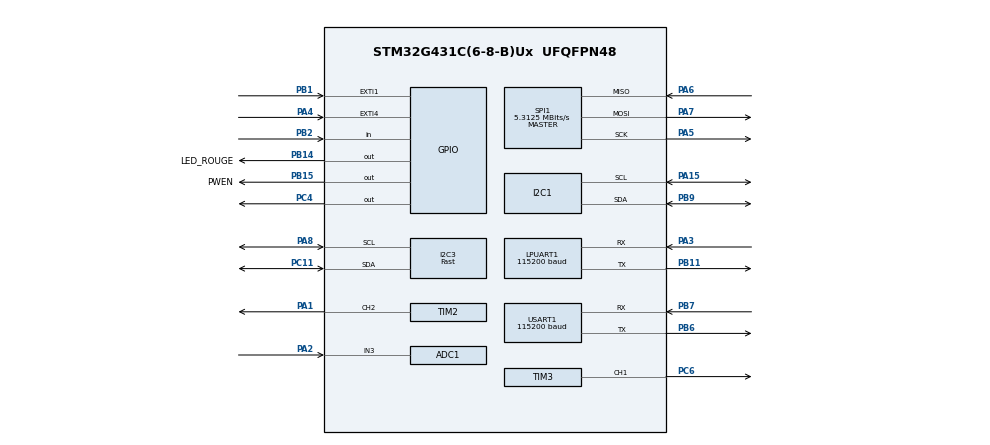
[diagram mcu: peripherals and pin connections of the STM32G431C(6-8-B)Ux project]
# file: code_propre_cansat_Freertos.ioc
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ADC1.Channel-0\#ChannelRegularConversion=ADC_CHANNEL_VREFINT
ADC1.Channel-1\#ChannelRegularConversion=ADC_CHANNEL_TEMPSENSOR_ADC1
ADC1.Channel-2\#ChannelRegularConversion=ADC_CHANNEL_3
ADC1.ContinuousConvMode=ENABLE
ADC1.EOCSelection=ADC_EOC_SEQ_CONV
ADC1.NbrOfConversion=3
ADC1.NbrOfConversionFlag=1
ADC1.OffsetNumber-0\#ChannelRegularConversion=ADC_OFFSET_NONE
ADC1.OffsetNumber-1\#ChannelRegularConversion=ADC_OFFSET_NONE
ADC1.OffsetNumber-2\#ChannelRegularConversion=ADC_OFFSET_NONE
ADC1.Rank-0\#ChannelRegularConversion=1
ADC1.Rank-1\#ChannelRegularConversion=2
ADC1.Rank-2\#ChannelRegularConversion=3
ADC1.SamplingTime-0\#ChannelRegularConversion=ADC_SAMPLETIME_640CYCLES_5
ADC1.SamplingTime-1\#ChannelRegularConversion=ADC_SAMPLETIME_640CYCLES_5
ADC1.SamplingTime-2\#ChannelRegularConversion=ADC_SAMPLETIME_640CYCLES_5
ADC1.master=1
Dma.ADC1.0.Direction=DMA_PERIPH_TO_MEMORY
Dma.ADC1.0.EventEnable=DISABLE
Dma.ADC1.0.Instance=DMA1_Channel2
Dma.ADC1.0.MemDataAlignment=DMA_MDATAALIGN_HALFWORD
Dma.ADC1.0.MemInc=DMA_MINC_ENABLE
Dma.ADC1.0.Mode=DMA_CIRCULAR
Dma.ADC1.0.PeriphDataAlignment=DMA_PDATAALIGN_HALFWORD
Dma.ADC1.0.PeriphInc=DMA_PINC_DISABLE
Dma.ADC1.0.Polarity=HAL_DMAMUX_REQ_GEN_RISING
Dma.ADC1.0.Priority=DMA_PRIORITY_LOW
Dma.ADC1.0.RequestNumber=1
Dma.ADC1.0.SignalID=NONE
Dma.ADC1.0.SyncEnable=DISABLE
Dma.ADC1.0.SyncPolarity=HAL_DMAMUX_SYNC_NO_EVENT
Dma.ADC1.0.SyncRequestNumber=1
Dma.ADC1.0.SyncSignalID=NONE
Dma.LPUART1_RX.1.Direction=DMA_PERIPH_TO_MEMORY
Dma.LPUART1_RX.1.EventEnable=DISABLE
Dma.LPUART1_RX.1.Instance=DMA1_Channel3
Dma.LPUART1_RX.1.MemDataAlignment=DMA_MDATAALIGN_BYTE
Dma.LPUART1_RX.1.MemInc=DMA_MINC_ENABLE
Dma.LPUART1_RX.1.Mode=DMA_CIRCULAR
Dma.LPUART1_RX.1.PeriphDataAlignment=DMA_PDATAALIGN_BYTE
Dma.LPUART1_RX.1.PeriphInc=DMA_PINC_DISABLE
Dma.LPUART1_RX.1.Polarity=HAL_DMAMUX_REQ_GEN_RISING
Dma.LPUART1_RX.1.Priority=DMA_PRIORITY_LOW
Dma.LPUART1_RX.1.RequestNumber=1
Dma.LPUART1_RX.1.SignalID=NONE
Dma.LPUART1_RX.1.SyncEnable=DISABLE
Dma.LPUART1_RX.1.SyncPolarity=HAL_DMAMUX_SYNC_NO_EVENT
Dma.LPUART1_RX.1.SyncRequestNumber=1
Dma.LPUART1_RX.1.SyncSignalID=NONE
Dma.LPUART1_TX.4.Direction=DMA_MEMORY_TO_PERIPH
Dma.LPUART1_TX.4.EventEnable=DISABLE
Dma.LPUART1_TX.4.Instance=DMA1_Channel4
Dma.LPUART1_TX.4.MemDataAlignment=DMA_MDATAALIGN_BYTE
Dma.LPUART1_TX.4.MemInc=DMA_MINC_ENABLE
Dma.LPUART1_TX.4.Mode=DMA_NORMAL
Dma.LPUART1_TX.4.PeriphDataAlignment=DMA_PDATAALIGN_BYTE
Dma.LPUART1_TX.4.PeriphInc=DMA_PINC_DISABLE
Dma.LPUART1_TX.4.Polarity=HAL_DMAMUX_REQ_GEN_RISING
Dma.LPUART1_TX.4.Priority=DMA_PRIORITY_LOW
Dma.LPUART1_TX.4.RequestNumber=1
Dma.LPUART1_TX.4.SignalID=NONE
Dma.LPUART1_TX.4.SyncEnable=DISABLE
Dma.LPUART1_TX.4.SyncPolarity=HAL_DMAMUX_SYNC_NO_EVENT
Dma.LPUART1_TX.4.SyncRequestNumber=1
Dma.LPUART1_TX.4.SyncSignalID=NONE
Dma.Request0=ADC1
Dma.Request1=LPUART1_RX
Dma.Request2=USART1_RX
Dma.Request3=TIM2_CH2
Dma.Request4=LPUART1_TX
Dma.TIM2_CH2.3.Direction=DMA_MEMORY_TO_PERIPH
Dma.TIM2_CH2.3.EventEnable=DISABLE
Dma.TIM2_CH2.3.Instance=DMA1_Channel1
Dma.TIM2_CH2.3.MemDataAlignment=DMA_MDATAALIGN_BYTE
Dma.TIM2_CH2.3.MemInc=DMA_MINC_ENABLE
Dma.TIM2_CH2.3.Mode=DMA_NORMAL
Dma.TIM2_CH2.3.PeriphDataAlignment=DMA_PDATAALIGN_WORD
Dma.TIM2_CH2.3.PeriphInc=DMA_PINC_DISABLE
Dma.TIM2_CH2.3.Polarity=HAL_DMAMUX_REQ_GEN_RISING
Dma.TIM2_CH2.3.Priority=DMA_PRIORITY_LOW
Dma.TIM2_CH2.3.RequestNumber=1
Dma.TIM2_CH2.3.SignalID=NONE
Dma.TIM2_CH2.3.SyncEnable=DISABLE
Dma.TIM2_CH2.3.SyncPolarity=HAL_DMAMUX_SYNC_NO_EVENT
Dma.TIM2_CH2.3.SyncRequestNumber=1
Dma.TIM2_CH2.3.SyncSignalID=NONE
Dma.USART1_RX.2.Direction=DMA_PERIPH_TO_MEMORY
Dma.USART1_RX.2.EventEnable=DISABLE
Dma.USART1_RX.2.Instance=DMA1_Channel5
Dma.USART1_RX.2.MemDataAlignment=DMA_MDATAALIGN_BYTE
Dma.USART1_RX.2.MemInc=DMA_MINC_ENABLE
Dma.USART1_RX.2.Mode=DMA_CIRCULAR
Dma.USART1_RX.2.PeriphDataAlignment=DMA_PDATAALIGN_BYTE
Dma.USART1_RX.2.PeriphInc=DMA_PINC_DISABLE
Dma.USART1_RX.2.Polarity=HAL_DMAMUX_REQ_GEN_RISING
Dma.USART1_RX.2.Priority=DMA_PRIORITY_LOW
Dma.USART1_RX.2.RequestNumber=1
Dma.USART1_RX.2.SignalID=NONE
Dma.USART1_RX.2.SyncEnable=DISABLE
Dma.USART1_RX.2.SyncPolarity=HAL_DMAMUX_SYNC_NO_EVENT
Dma.USART1_RX.2.SyncRequestNumber=1
Dma.USART1_RX.2.SyncSignalID=NONE
FATFS._MAX_SS=512
FATFS._USE_LFN=0
FREERTOS.BinarySemaphores01=uartTxDone,Dynamic,NULL,Available
FREERTOS.INCLUDE_vTaskDelayUntil=1
FREERTOS.Mutexes01=SDCard_mutexe,Dynamic,NULL,Depleted;I2Cmutex,Dynamic,NULL,Depleted;uartmutex,Dynamic,NULL,Available
FREERTOS.Tasks01=statemachine,1,300,Startstatemachine,Default,NULL,Dynamic,NULL,NULL;GNSSParse,0,256,StartGNSSParse,Default,NULL,Dynamic,NULL,NULL;Sdcardwrite,0,512,StartSdcard,Default,NULL,Dynamic,NULL,NULL;servo,1,256,Startservo,Default,NULL,Dynamic,NULL,NULL;distancecalc,-1,256,Startdistancecalc,Default,NULL,Dynamic,NULL,NULL;tarvosDecode,3,256,startTarvosDecode,Default,NULL,Dynamic,NULL,NULL
FREERTOS.configENABLE_FPU=1
FREERTOS.configTOTAL_HEAP_SIZE=12000
FREERTOS.configUSE_NEWLIB_REENTRANT=1
I2C1.Timing=0x40B285C2
I2C3.I2C_Speed_Mode=I2C_Fast
I2C3.Timing=0x40621236
LPUART1.BaudRate=115200
Mcu.Family=STM32G4
Mcu.Name=STM32G431C(6-8-B)Ux
Mcu.Package=UFQFPN48
NVIC.ADC1_2_IRQn=true\:5\:0\:false\:false\:true\:true\:true\:true\:true
NVIC.DMA1_Channel1_IRQn=true\:5\:0\:false\:false\:true\:true\:false\:true\:true
NVIC.DMA1_Channel2_IRQn=true\:5\:0\:false\:false\:true\:true\:false\:true\:true
NVIC.DMA1_Channel3_IRQn=true\:5\:0\:false\:false\:true\:true\:false\:true\:true
NVIC.DMA1_Channel4_IRQn=true\:5\:0\:false\:false\:true\:true\:false\:true\:true
NVIC.DMA1_Channel5_IRQn=true\:5\:0\:false\:false\:true\:true\:false\:true\:true
NVIC.EXTI1_IRQn=true\:5\:0\:false\:false\:true\:true\:true\:true\:true
NVIC.EXTI4_IRQn=true\:5\:0\:false\:false\:true\:true\:true\:true\:true
NVIC.LPUART1_IRQn=true\:5\:0\:false\:false\:true\:true\:true\:true\:true
NVIC.PriorityGroup=NVIC_PRIORITYGROUP_4
NVIC.TIM1_UP_TIM16_IRQn=true\:15\:0\:false\:false\:true\:false\:false\:true\:true
NVIC.TIM2_IRQn=true\:5\:0\:false\:false\:true\:true\:true\:true\:true
NVIC.TIM4_IRQn=true\:6\:0\:true\:false\:true\:true\:true\:true\:true
NVIC.TimeBase=TIM1_UP_TIM16_IRQn
NVIC.TimeBaseIP=TIM1
NVIC.USART1_IRQn=true\:5\:0\:false\:false\:true\:true\:true\:true\:true
PA1.GPIO_Speed=GPIO_SPEED_FREQ_MEDIUM
PA1.Signal=S_TIM2_CH2
PA13.Mode=Trace_Asynchronous_SW
PA13.Signal=SYS_JTMS-SWDIO
PA14.Mode=Trace_Asynchronous_SW
PA14.Signal=SYS_JTCK-SWCLK
PA15.Mode=I2C
PA15.Signal=I2C1_SCL
PA2.Mode=IN3-Single-Ended
PA2.Signal=ADC1_IN3
PA3.Mode=Asynchronous
PA3.Signal=LPUART1_RX
PA4.GPIO_ModeDefaultEXTI=GPIO_MODE_IT_RISING_FALLING
PA4.Signal=GPXTI4
PA5.GPIO_PuPd=GPIO_NOPULL
PA5.Mode=Full_Duplex_Master
PA5.Signal=SPI1_SCK
PA6.GPIO_PuPd=GPIO_NOPULL
PA6.Mode=Full_Duplex_Master
PA6.Signal=SPI1_MISO
PA7.GPIO_PuPd=GPIO_NOPULL
PA7.Mode=Full_Duplex_Master
PA7.Signal=SPI1_MOSI
PA8.Mode=I2C
PA8.Signal=I2C3_SCL
PB1.GPIO_ModeDefaultEXTI=GPIO_MODE_IT_RISING_FALLING
PB1.GPIO_PuPd=GPIO_NOPULL
PB1.Signal=GPXTI1
PB11.Mode=Asynchronous
PB11.Signal=LPUART1_TX
PB14.GPIO_Label=LED_ROUGE
PB14.Signal=GPIO_Output
PB15.GPIO_Label=PWEN
PB15.Signal=GPIO_Output
PB2.Signal=GPIO_Input
PB3.Mode=Trace_Asynchronous_SW
PB3.Signal=SYS_JTDO-SWO
PB6.Mode=Asynchronous
PB6.Signal=USART1_TX
PB7.Mode=Asynchronous
PB7.Signal=USART1_RX
PB9.Mode=I2C
PB9.Signal=I2C1_SDA
PC11.Mode=I2C
PC11.Signal=I2C3_SDA
PC4.Signal=GPIO_Output
PC6.Signal=S_TIM3_CH1
PF0-OSC_IN.Mode=HSE-External-Oscillator
PF0-OSC_IN.Signal=RCC_OSC_IN
PF1-OSC_OUT.Mode=HSE-External-Oscillator
PF1-OSC_OUT.Signal=RCC_OSC_OUT
ProjectManager.HeapSize=0x200
ProjectManager.StackSize=0x400
ProjectManager.TargetToolchain=STM32CubeIDE
RCC.ADC12Freq_Value=170000000
RCC.AHBFreq_Value=170000000
RCC.APB1Freq_Value=170000000
RCC.APB1TimFreq_Value=170000000
RCC.APB2Freq_Value=170000000
RCC.APB2TimFreq_Value=170000000
RCC.CortexFreq_Value=170000000
RCC.EXTERNAL_CLOCK_VALUE=12288000
RCC.HCLKFreq_Value=170000000
RCC.HSE_VALUE=16000000
RCC.HSI48_VALUE=48000000
RCC.HSI_VALUE=16000000
RCC.LSE_VALUE=32768
RCC.PLLM=RCC_PLLM_DIV4
RCC.PLLN=85
RCC.PLLSourceVirtual=RCC_PLLSOURCE_HSE
RCC.SYSCLKFreq_VALUE=170000000
RCC.SYSCLKSource=RCC_SYSCLKSOURCE_PLLCLK
RCC.USBFreq_Value=170000000
RCC.VCOOutputFreq_Value=340000000
SH.S_TIM2_CH2.0=TIM2_CH2,PWM Generation2 CH2
SH.S_TIM3_CH1.0=TIM3_CH1,PWM Generation1 CH1
SPI1.BaudRatePrescaler=SPI_BAUDRATEPRESCALER_32
SPI1.CalculateBaudRate=5.3125 MBits/s
SPI1.DataSize=SPI_DATASIZE_8BIT
SPI1.Direction=SPI_DIRECTION_2LINES
SPI1.Mode=SPI_MODE_MASTER
SPI1.VirtualType=VM_MASTER
TIM2.Channel-PWM\ Generation2\ CH2=TIM_CHANNEL_2
TIM2.OCFastMode_PWM-PWM\ Generation2\ CH2=TIM_OCFAST_ENABLE
TIM2.PeriodNoDither=204-1
TIM2.Prescaler=0
TIM3.AutoReloadPreload=TIM_AUTORELOAD_PRELOAD_ENABLE
TIM3.Channel-PWM\ Generation1\ CH1=TIM_CHANNEL_1
TIM3.PeriodNoDither=10000-1
TIM3.Prescaler=170-1
TIM4.PeriodNoDither=2000-1
TIM4.Prescaler=17000-1
USART1.BaudRate=115200
USART1.VirtualMode-Asynchronous=VM_ASYNC
VP_ADC1_TempSens_Input.Mode=IN-TempSens
VP_ADC1_Vref_Input.Mode=IN-Vrefint
VP_FATFS_VS_Generic.Mode=User_defined
VP_FREERTOS_VS_CMSIS_V1.Mode=CMSIS_V1
VP_SYS_VS_DBSignals.Mode=DisableDeadBatterySignals
VP_SYS_VS_tim1.Mode=TIM1
VP_TIM2_VS_ClockSourceINT.Mode=Internal
VP_TIM3_VS_ClockSourceINT.Mode=Internal
VP_TIM4_VS_ClockSourceINT.Mode=Internal
board=custom

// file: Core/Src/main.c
/* USER CODE BEGIN Header */
/**
  ******************************************************************************
  * @file           : main.c
  * @brief          : Main program body
  ******************************************************************************
  * @attention
  *
  * Copyright (c) 2025 STMicroelectronics.
  * All rights reserved.
  *
  * This software is licensed under terms that can be found in the LICENSE file
  * in the root directory of this software component.
  * If no LICENSE file comes with this software, it is provided AS-IS.
  *
  ******************************************************************************
  */
/* USER CODE END Header */
#include "main.h"
#include "cmsis_os.h"
#include "adc.h"
#include "dma.h"
#include "app_fatfs.h"
#include "i2c.h"
#include "usart.h"
#include "spi.h"
#include "tim.h"
#include "gpio.h"

/* USER CODE BEGIN Includes */
#include "bmp581.h"
#include "6axis.h"
#include "tarvos.h"
#include "led.h"
#include "statemachine.h"
#include "servo.h"
#include "ssd1306.h"
#include "math.h"
#include "GNSS.h"
/* USER CODE END Includes */

/* USER CODE BEGIN PV */
int tbtn1=0;

uint16_t rawADCdata[3];
float temp=0;
float vrefint=0;
float vbat=0;

uint8_t tarvos_TX_Buffer[TarvosTxBufferSize];
uint8_t tarvos_DATA[64];
uint8_t tarvos_RX_Buffer[TarvosRxBufferSize];

uint8_t workingbuffer[110];
uint8_t sdcardbuffer[256];
AXIS6 myData6AXIS;
BMP_t myDatabmp581;

FATFS fs;
FATFS *pfs;
FIL fil;
FRESULT fres;
DWORD fre_clust;
uint32_t total, free1;

#ifdef PARTIE_BAS
DecodedPayload TOPData;
#endif

DecodedPayload OTHERData;

GNSS_StateHandle GNSSData;

uint8_t LEDDMABUF[DMABUFLEN];
uint8_t DMA_COMPLETE_FLAG=0;

int gros_btn_time=0;

STATE state=IDLE;

int flag_drop = 0;
int flag_separation = 0;
int flag_calib=0;
int flag_bouton_servo=0;
int flag_servo_started=0;
int sd_detect_flag=0;

float hauteur_Initiale=0.0;

float hauteur_servo=0.0;

int pbmseeker=0;

int received_flag=0;

int trameready=0;

/* USER CODE END PV */

void SystemClock_Config(void);
void MX_FREERTOS_Init(void);

/* USER CODE BEGIN 0 */
void HAL_GPIO_EXTI_Callback(uint16_t GPIO_Pin)//lors d'un appuie sur un bouton, le systeme s'interrompt afin d'arriver dans cette fonction redefinie avec en parametre d'entre , le bouton sur lequel l'on a appuiyé
{
	if(GPIO_Pin==GPIO_PIN_4){
		if(HAL_GPIO_ReadPin(GPIOA,GPIO_PIN_4)== GPIO_PIN_SET){

						gros_btn_time=0;
						tbtn1=HAL_GetTick();

					}
					else{

						gros_btn_time=(HAL_GetTick()-tbtn1);

		if(gros_btn_time<=380){
#ifdef PARTIE_HAUT
			flag_bouton_servo=0;
#endif

							}
					if(gros_btn_time>=400 && gros_btn_time<=2000){
#ifdef PARTIE_HAUT
						flag_bouton_servo=1;
#endif
					}
					if(gros_btn_time>=2500 && gros_btn_time<=3500){
#ifdef PARTIE_HAUT
						hauteur_Initiale=myDatabmp581.altitude;
						create_and_send_payload((uint8_t *) tarvos_TX_Buffer,CHANNEL,BOTTOM_ADDR,0x20,0,0,0.0,0.0,0.0,hauteur_Initiale,0.0,0.0,0);
						flag_calib=1;
#endif

										}
					if(gros_btn_time>=4000){
											HAL_GPIO_TogglePin(PWEN_GPIO_Port,PWEN_Pin);
											gros_btn_time=0;

															}

					gros_btn_time=0;
					}

	}

//	if(GPIO_Pin==GPIO_PIN_0){
//		flag_drop=1;
//
//		}

	}
void HAL_TIM_PWM_PulseFinishedCallback(TIM_HandleTypeDef *htim){

	LED_Callback();
}
/* USER CODE END 0 */

int main(void)
{

  /* MCU Configuration--------------------------------------------------------*/

  /* Reset of all peripherals, Initializes the Flash interface and the Systick. */
  HAL_Init();

  /* Configure the system clock */
  SystemClock_Config();

  /* Initialize all configured peripherals */
  MX_GPIO_Init();
  MX_DMA_Init();
  MX_ADC1_Init();
  MX_I2C1_Init();
  MX_I2C3_Init();
  MX_LPUART1_UART_Init();
  MX_USART1_UART_Init();
  MX_TIM3_Init();
  MX_TIM2_Init();
  MX_SPI1_Init();
  if (MX_FATFS_Init() != APP_OK) {
    Error_Handler();
  }
  MX_TIM4_Init();
  /* USER CODE BEGIN 2 */

  ssd1306_Init();
  ssd1306_Fill(Black);
  ssd1306_SetCursor(32, 40);
  ssd1306_WriteString("Init...", Font_7x10, White);
  ssd1306_UpdateScreen();

  HAL_GPIO_WritePin(PWEN_GPIO_Port,PWEN_Pin,GPIO_PIN_SET);
  HAL_GPIO_WritePin(LED_ROUGE_GPIO_Port,LED_ROUGE_Pin,GPIO_PIN_SET);

#ifdef PARTIE_HAUT
  if( release_mecanism()!=HAL_OK){
	  ssd1306_SetCursor(32, 40);
 	  ssd1306_Fill(Black);
 	  ssd1306_WriteString("servopbm", Font_7x10, White);
 	  ssd1306_UpdateScreen();
 	  HAL_Delay(500);
 	 pbmseeker=1;

   }
  flag_servo_started=1;

#endif

  if(HAL_ADC_Start_DMA(&hadc1,(uint16_t*)rawADCdata, 3)!=HAL_OK){
	  ssd1306_SetCursor(32, 40);
 	  ssd1306_Fill(Black);
 	  ssd1306_WriteString("adcpbm", Font_7x10, White);
 	  ssd1306_UpdateScreen();
 	  HAL_Delay(500);
 	 pbmseeker=1;

   }

   HAL_Delay(100);
   HAL_UART_Abort(&huart1);
   if( HAL_UART_Receive_DMA(&huart1, (uint8_t *)workingbuffer, 100)!=HAL_OK){
	   ssd1306_SetCursor(32, 40);
  	  ssd1306_Fill(Black);
  	  ssd1306_WriteString("gpspbm", Font_7x10, White);
  	  ssd1306_UpdateScreen();
  	  HAL_Delay(500);
  	pbmseeker=1;

    }

  if(  LED_Init()!=HAL_OK){
	  ssd1306_SetCursor(32, 40);
 	  ssd1306_Fill(Black);
 	  ssd1306_WriteString("ledpbm", Font_7x10, White);
 	  ssd1306_UpdateScreen();
 	  HAL_Delay(500);
 	 pbmseeker=1;

   }
  Init_HighPerf_Mode_6_axis();

  if(bmp581_init_precise_normal(&myDatabmp581)!=HAL_OK){
	  ssd1306_SetCursor(32, 40);
 	  ssd1306_Fill(Black);
 	  ssd1306_WriteString("bmp pbm", Font_7x10, White);
 	  ssd1306_UpdateScreen();
 	  HAL_Delay(500);
 	 pbmseeker=1;

   }

  //mon adresse est 1° et on envoit à 2°
#ifdef PARTIE_BAS
  if( INIT_PERM_TARVOS(BOTTOM_ADDR, GROUND_ADDR)!=HAL_OK){
	  ssd1306_SetCursor(32, 40);
 	  ssd1306_Fill(Black);
 	  ssd1306_WriteString("tvsaddrpbm", Font_7x10, White);
 	  ssd1306_UpdateScreen();
 	  HAL_Delay(500);
 	 pbmseeker=1;

   }
#endif

#ifdef PARTIE_HAUT
  if( INIT_PERM_TARVOS(TOP_ADDR, BOTTOM_ADDR)!=HAL_OK){
	  ssd1306_SetCursor(32, 40);
 	  ssd1306_Fill(Black);
 	  ssd1306_WriteString("tvsaddrpbm", Font_7x10, White);
 	  ssd1306_UpdateScreen();
 	  HAL_Delay(500);
 	 pbmseeker=1;

   }
#endif

  HAL_Delay(100);
  HAL_UART_Abort(&hlpuart1);
  if(HAL_UART_Receive_DMA(&hlpuart1, (uint8_t *)tarvos_RX_Buffer,5)!=HAL_OK){
	   ssd1306_SetCursor(32, 40);
 	  ssd1306_Fill(Black);
 	  ssd1306_WriteString("tvsrxpbm", Font_7x10, White);
 	  ssd1306_UpdateScreen();
 	  HAL_Delay(500);
 	pbmseeker=1;

   }

//
//  f_mount(&fs, "", 0);
//
//     /* Open file to write */
//  f_open(&fil, "cansat.txt", FA_CREATE_ALWAYS | FA_READ | FA_WRITE);
//
//     /* Check free space */
//  f_getfree("", &fre_clust, &pfs);
//
//  total = (uint32_t)((pfs->n_fatent - 2) * pfs->csize * 0.5);
//  free1 = (uint32_t)(fre_clust * pfs->csize * 0.5);
//
//
//     /* Writing text */
//     f_puts("startofcansat\n", &fil);
//     HAL_Delay(100);
//
//     f_close(&fil);
//     f_mount(NULL, "", 1);
//

  if(pbmseeker==0){
	  ssd1306_SetCursor(32, 40);

	  ssd1306_Fill(Black);
	  ssd1306_WriteString("done!", Font_7x10, White);
	  ssd1306_UpdateScreen();
	  HAL_Delay(500);

  }
  if(pbmseeker==1){

	  ssd1306_SetCursor(32, 40);

	  ssd1306_Fill(Black);
	  ssd1306_WriteString("PROBLEM", Font_7x10, White);
	  ssd1306_UpdateScreen();
	  HAL_Delay(2000);

  }
  int r=0;
  int g=0;
  int b=0;
  int t=0;

  /* USER CODE END 2 */

  /* Call init function for freertos objects (in cmsis_os2.c) */
  MX_FREERTOS_Init();

  /* Start scheduler */
  osKernelStart();

  /* We should never get here as control is now taken by the scheduler */

  /* Infinite loop */
  /* USER CODE BEGIN WHILE */
  while (1)
  {

	  LED_Setcolour(r, g, b,r, g, b);
	  r=floor(abs(255*cosf((2*M_PI/255)*t)));
	  g=floor(abs(255*cosf((2*M_PI/255)*t+(180/M_PI))));
	  b=floor(abs(255*cosf((2*M_PI/255)*t+(270/M_PI))));

	  if(t>=255){
		  t=0;
	  }
	  t++;

	  LED_Update();

    /* USER CODE END WHILE */

  }
}

void SystemClock_Config(void)
{
  RCC_OscInitTypeDef RCC_OscInitStruct = {0};
  RCC_ClkInitTypeDef RCC_ClkInitStruct = {0};

  /** Configure the main internal regulator output voltage
  */
  HAL_PWREx_ControlVoltageScaling(PWR_REGULATOR_VOLTAGE_SCALE1);

  /** Initializes the RCC Oscillators according to the specified parameters
  * in the RCC_OscInitTypeDef structure.
  */
  RCC_OscInitStruct.OscillatorType = RCC_OSCILLATORTYPE_HSE;
  RCC_OscInitStruct.HSEState = RCC_HSE_ON;
  RCC_OscInitStruct.PLL.PLLState = RCC_PLL_ON;
  RCC_OscInitStruct.PLL.PLLSource = RCC_PLLSOURCE_HSE;
  RCC_OscInitStruct.PLL.PLLM = RCC_PLLM_DIV2;
  RCC_OscInitStruct.PLL.PLLN = 25;
  RCC_OscInitStruct.PLL.PLLP = RCC_PLLP_DIV2;
  RCC_OscInitStruct.PLL.PLLQ = RCC_PLLQ_DIV2;
  RCC_OscInitStruct.PLL.PLLR = RCC_PLLR_DIV2;
  if (HAL_RCC_OscConfig(&RCC_OscInitStruct) != HAL_OK)
  {
    Error_Handler();
  }

  /** Initializes the CPU, AHB and APB buses clocks
  */
  RCC_ClkInitStruct.ClockType = RCC_CLOCKTYPE_HCLK|RCC_CLOCKTYPE_SYSCLK
                              |RCC_CLOCKTYPE_PCLK1|RCC_CLOCKTYPE_PCLK2;
  RCC_ClkInitStruct.SYSCLKSource = RCC_SYSCLKSOURCE_PLLCLK;
  RCC_ClkInitStruct.AHBCLKDivider = RCC_SYSCLK_DIV1;
  RCC_ClkInitStruct.APB1CLKDivider = RCC_HCLK_DIV1;
  RCC_ClkInitStruct.APB2CLKDivider = RCC_HCLK_DIV1;

  if (HAL_RCC_ClockConfig(&RCC_ClkInitStruct, FLASH_LATENCY_3) != HAL_OK)
  {
    Error_Handler();
  }
}

void HAL_TIM_PeriodElapsedCallback(TIM_HandleTypeDef *htim)
{
  if (htim->Instance == TIM1)
  {
    HAL_IncTick();
  }
}

void Error_Handler(void)
{
  __disable_irq();
  while (1)
  {
  }
}

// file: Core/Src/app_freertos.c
/* USER CODE BEGIN Header */
/**
  ******************************************************************************
  * File Name          : app_freertos.c
  * Description        : Code for freertos applications
  ******************************************************************************
  * @attention
  *
  * Copyright (c) 2025 STMicroelectronics.
  * All rights reserved.
  *
  * This software is licensed under terms that can be found in the LICENSE file
  * in the root directory of this software component.
  * If no LICENSE file comes with this software, it is provided AS-IS.
  *
  ******************************************************************************
  */
/* USER CODE END Header */

#include "FreeRTOS.h"
#include "task.h"
#include "main.h"
#include "cmsis_os.h"

/* USER CODE BEGIN Includes */
#include "bmp581.h"
#include "6axis.h"
#include "tarvos.h"
#include "led.h"
#include "statemachine.h"
#include "servo.h"
#include "ssd1306.h"
#include "math.h"
#include "usart.h"
#include "GNSS.h"
#include "app_fatfs.h"
#include "sd_app.h"
/* USER CODE END Includes */

/* USER CODE BEGIN Variables */

extern uint16_t rawADCdata[3];
extern float temp;
extern float vrefint;
extern float vbat;

extern uint8_t tarvos_TX_Buffer[TarvosTxBufferSize];
extern uint8_t tarvos_DATA[64];
extern uint8_t tarvos_RX_Buffer[TarvosRxBufferSize];
extern uint8_t sdcardbuffer[512];
extern uint8_t workingbuffer[110];

extern uint8_t dma_rx_buffer[DMA_CHUNK_SIZE];               // Réception DMA par bloc de 5
extern uint8_t circular_buffer[CIRC_BUF_SIZE];              // Buffer circulaire
extern volatile uint16_t write_index;
extern volatile uint16_t read_index;

extern AXIS6 myData6AXIS;
extern BMP_t myDatabmp581;
extern GNSS_StateHandle GNSSData;

extern double P0;

extern GNSS_StateHandle GNSSData;

extern uint8_t LEDDMABUF[DMABUFLEN];
extern uint8_t DMA_COMPLETE_FLAG;

extern STATE state;

extern int flag_drop;
extern int flag_separation;
extern int flag_calib;

extern int flag_bouton_servo;
extern float hauteur_Initiale;

extern float hauteur_relative;

extern int pbmseeker;

extern int trameready;

extern int flag_servo_started;

extern int received_flag;

int counterrecalib=0;
int sd_counter=0;

#ifdef PARTIE_BAS
extern DecodedPayload TOPData;
float distance_entre_module=0.0;
#endif

extern DecodedPayload OTHERData;

int pbmseeker_flag=0;
int blinker_sd_flag=0;

extern uint32_t timeindex;

extern uint32_t cpt_tps_chute;
extern int flag_fin;

UBaseType_t sizestatemachine;
UBaseType_t sizeGNSS;
UBaseType_t sizesdcard;
UBaseType_t sizetarvos;

float timestatemachine=0.0;
float timesdcard=0.0;
float timedecode=0.0;
float timeservo=0.0;
float timedist=0.0;
float timeGNSS=0.0;

extern FATFS FatFs;   // FATFS handle
extern FILINFO fno;	  // Structure holds information
extern FATFS *getFreeFs; 	  // Read information
extern FIL fil;
extern DIR dir;			  // Directory object structure
extern DWORD free_clusters;  // Free Clusters
extern DWORD free_sectors;	  // Free Sectors
extern DWORD total_sectors;

/* USER CODE END Variables */
osThreadId statemachineHandle;
osThreadId GNSSParseHandle;
osThreadId SdcardwriteHandle;
osThreadId servoHandle;
osThreadId distancecalcHandle;
osThreadId tarvosDecodeHandle;
osMutexId SDCard_mutexeHandle;
osMutexId I2CmutexHandle;
osMutexId uartmutexHandle;
osSemaphoreId uartTxDoneHandle;

void Startstatemachine(void const * argument);
void StartGNSSParse(void const * argument);
void StartSdcard(void const * argument);
void Startservo(void const * argument);
void Startdistancecalc(void const * argument);
void startTarvosDecode(void const * argument);

void MX_FREERTOS_Init(void); /* (MISRA C 2004 rule 8.1) */

void MX_FREERTOS_Init(void) {
  /* Create the mutex(es) */
  /* definition and creation of SDCard_mutexe */
  osMutexDef(SDCard_mutexe);
  SDCard_mutexeHandle = osMutexCreate(osMutex(SDCard_mutexe));

  /* definition and creation of I2Cmutex */
  osMutexDef(I2Cmutex);
  I2CmutexHandle = osMutexCreate(osMutex(I2Cmutex));

  /* definition and creation of uartmutex */
  osMutexDef(uartmutex);
  uartmutexHandle = osMutexCreate(osMutex(uartmutex));

  /* Create the semaphores(s) */
  /* definition and creation of uartTxDone */
  osSemaphoreDef(uartTxDone);
  uartTxDoneHandle = osSemaphoreCreate(osSemaphore(uartTxDone), 1);

  /* USER CODE BEGIN RTOS_SEMAPHORES */
  osSemaphoreWait(uartTxDoneHandle, 0);
  /* add semaphores, ... */
  /* USER CODE END RTOS_SEMAPHORES */

  /* Create the thread(s) */
  /* definition and creation of statemachine */
  osThreadDef(statemachine, Startstatemachine, osPriorityAboveNormal, 0, 300);
  statemachineHandle = osThreadCreate(osThread(statemachine), NULL);

  /* definition and creation of GNSSParse */
  osThreadDef(GNSSParse, StartGNSSParse, osPriorityNormal, 0, 256);
  GNSSParseHandle = osThreadCreate(osThread(GNSSParse), NULL);

  /* definition and creation of Sdcardwrite */
  osThreadDef(Sdcardwrite, StartSdcard, osPriorityNormal, 0, 512);
  SdcardwriteHandle = osThreadCreate(osThread(Sdcardwrite), NULL);

  /* definition and creation of servo */
  osThreadDef(servo, Startservo, osPriorityAboveNormal, 0, 256);
  servoHandle = osThreadCreate(osThread(servo), NULL);

  /* definition and creation of distancecalc */
  osThreadDef(distancecalc, Startdistancecalc, osPriorityBelowNormal, 0, 256);
  distancecalcHandle = osThreadCreate(osThread(distancecalc), NULL);

  /* definition and creation of tarvosDecode */
  osThreadDef(tarvosDecode, startTarvosDecode, osPriorityRealtime, 0, 256);
  tarvosDecodeHandle = osThreadCreate(osThread(tarvosDecode), NULL);

  /* USER CODE BEGIN RTOS_THREADS */
#ifdef PARTIE_HAUT

  osThreadSuspend(distancecalcHandle);

#endif
#ifdef PARTIE_BAS

  osThreadSuspend(servoHandle);

#endif

  CoreDebug->DEMCR |=CoreDebug_DEMCR_TRCENA_Msk;
  DWT->CYCCNT =0;
  DWT->CTRL |= DWT_CTRL_CYCCNTENA_Msk;

  /* add threads, ... */
  /* USER CODE END RTOS_THREADS */

}

void Startstatemachine(void const * argument)
{
  /* USER CODE BEGIN Startstatemachine */
	TickType_t xLastWakeTime = xTaskGetTickCount();
  /* Infinite loop */
  for(;;)
  {

	  uint32_t start1= DWT->CYCCNT;
      if (osMutexWait(I2CmutexHandle, 20) == osOK)
      {

	  if(pbmseeker_flag==0){
		  if(pbmseeker==0){
			  ssd1306_SetCursor(32, 40);
			  ssd1306_Fill(Black);
			  ssd1306_WriteString("OK!", Font_16x24, White);
			  ssd1306_UpdateScreen();

		  }
		  if(pbmseeker==1){
			  ssd1306_SetCursor(32, 40);
			  ssd1306_Fill(Black);
			  ssd1306_WriteString("PB!", Font_16x24, White);
			  ssd1306_UpdateScreen();

		  }
		  vTaskDelay(pdMS_TO_TICKS(500));
		  pbmseeker_flag=1;
	  }
	  else{
	  statemachine();
	  ssd1306_UpdateScreen();
	  }

      osMutexRelease(I2CmutexHandle);
  }

	  sizestatemachine=uxTaskGetStackHighWaterMark(statemachineHandle);
	  sizeGNSS=uxTaskGetStackHighWaterMark(GNSSParseHandle);
	  sizesdcard=uxTaskGetStackHighWaterMark(SdcardwriteHandle);
	  sizetarvos=uxTaskGetStackHighWaterMark(tarvosDecodeHandle);

	  uint32_t end1= DWT->CYCCNT;
	  uint32_t cycles= end1-start1;

	  timestatemachine=(float) cycles/(SystemCoreClock/1000000.0f);

	  vTaskDelayUntil(&xLastWakeTime, pdMS_TO_TICKS(200));
  }
  /* USER CODE END Startstatemachine */
}

void StartGNSSParse(void const * argument)
{
  /* USER CODE BEGIN StartGNSSParse */
	TickType_t xLastWakeTime = xTaskGetTickCount();
  /* Infinite loop */
  for(;;)
  {
	  uint32_t start1= DWT->CYCCNT;
	  GNSS_ParsePVTData(&GNSSData);
	  bmp581_read_precise_normal(&myDatabmp581);
      if (osMutexWait(I2CmutexHandle, 20) == osOK)
      {
    	  Read_sensor_data(&myData6AXIS);
          osMutexRelease(I2CmutexHandle);
      }

	  if(flag_calib){
		  hauteur_relative=(float)(myDatabmp581.altitude-hauteur_Initiale);
	  }

		if(flag_fin==1){

			osThreadSuspend(NULL);
		}

		  uint32_t end1= DWT->CYCCNT;
		  uint32_t cycles= end1-start1;

		  float times=(float) cycles/(SystemCoreClock/1000000.0f);
if(times>timeGNSS){
	timeGNSS=times;
}

vTaskDelayUntil(&xLastWakeTime, pdMS_TO_TICKS(100));
  }
  /* USER CODE END StartGNSSParse */
}

void StartSdcard(void const * argument)
{
  /* USER CODE BEGIN StartSdcard */

	FRESULT fres=FR_OK;
	fres = f_mount(&FatFs, "", 1);
	TickType_t xLastWakeTime = xTaskGetTickCount();
  /* Infinite loop */
  for(;;)
  {
	  uint32_t start1= DWT->CYCCNT;
		  osMutexWait(SDCard_mutexeHandle, portMAX_DELAY);

		  blinker_sd_flag=1-blinker_sd_flag;
		  if(blinker_sd_flag==1){
			  LED_Setcolour(0,0,0,255,255,255);
		  }
		  else{
			  LED_Setcolour(0,0,0,0,0,0);
		  }

		  if(flag_drop==0){

			  if(sd_counter==5){
				  fres=store_in_sd(fres);

			  sd_counter=0;
			  }
			  sd_counter++;

		  }
		  else{
			  fres=store_in_sd(fres);

		  }

		  osMutexRelease(SDCard_mutexeHandle);

			if(flag_fin==1){

				f_mount(NULL, "", 0);
				osThreadSuspend(NULL);
			}

			  uint32_t end1= DWT->CYCCNT;
			  uint32_t cycles= end1-start1;
			  timesdcard=(float) cycles/(SystemCoreClock/1000000.0f);

			  vTaskDelayUntil(&xLastWakeTime, pdMS_TO_TICKS(200));
  }
  /* USER CODE END StartSdcard */
}

void Startservo(void const * argument)
{
  /* USER CODE BEGIN Startservo */
	TickType_t xLastWakeTime = xTaskGetTickCount();
  /* Infinite loop */
  for(;;)
  {
	  uint32_t start1= DWT->CYCCNT;

	  if((flag_drop==1) && (flag_calib==1)){

		  if((hauteur_relative<=HAUTEUR_SEPARATION)){
			  release_mecanism();
			  flag_separation=1;
			  flag_servo_started=1;
			  vTaskDelay(pdMS_TO_TICKS(500));
			  osThreadSuspend(NULL);

		  }
	  }
	  if(flag_drop==0){
		  if(flag_bouton_servo==1){
			  release_mecanism();
			  flag_bouton_servo=2;
			  flag_servo_started=1;
		  }
		  if(flag_bouton_servo==0){
			  lock_mecanism();
			  flag_bouton_servo=2;
			  flag_servo_started=1;
		  }

	  }

	  	  if(flag_servo_started==1){
	  		 vTaskDelay(pdMS_TO_TICKS(500));

	  		  stop_servo();
	  		  flag_servo_started=0;
	  	  }

		if(flag_fin==1){

			osThreadSuspend(NULL);
		}

		  uint32_t end1= DWT->CYCCNT;
		  uint32_t cycles= end1-start1;
		  float times=(float) cycles/(SystemCoreClock/1000000.0f);
if(times>timeservo){
	timeservo=times;
}
vTaskDelayUntil(&xLastWakeTime, pdMS_TO_TICKS(200));
  }
  /* USER CODE END Startservo */
}

void Startdistancecalc(void const * argument)
{
  /* USER CODE BEGIN Startdistancecalc */
	TickType_t xLastWakeTime = xTaskGetTickCount();
  /* Infinite loop */
  for(;;)
  {
	  uint32_t start1= DWT->CYCCNT;

	  if(flag_calib==1){

		  if(GNSSData.fixType>=3){
#ifdef PARTIE_BAS
			  distance_entre_module=distancecalc(GNSSData.fLat,TOPData.latitude, GNSSData.fLon,TOPData.longitude,hauteur_relative,TOPData.altitude_baro);

#endif
	  }
}

		if(flag_fin==1){

			osThreadSuspend(NULL);
		}

	  uint32_t end1= DWT->CYCCNT;
	  uint32_t cycles= end1-start1;

	  float times=(float) cycles/(SystemCoreClock/1000000.0f);
if(times>timedist){
timedist=times;
}
vTaskDelayUntil(&xLastWakeTime, pdMS_TO_TICKS(200));
  }
  /* USER CODE END Startdistancecalc */
}

void startTarvosDecode(void const * argument)
{
  /* USER CODE BEGIN startTarvosDecode */
	TickType_t xLastWakeTime = xTaskGetTickCount();
	 uint8_t temp_trame[TRAME_SIZE];
		      uint8_t temp5[5];
		      uint8_t data_index = 0;
  /* Infinite loop */
  for(;;)
  {
	  uint32_t start1= DWT->CYCCNT;

	          while (read_index != write_index) {
	              // Recherche de l'entête principale
	              if (circular_buffer[read_index] == 0x02 &&
	                  circular_buffer[(read_index + 1) % CIRC_BUF_SIZE] == 0x81)
	              {
	                  data_index = 0;

	                  while (data_index < TRAME_SIZE) {
	                      // Vérifie s’il reste au moins 5 octets
	                      uint16_t available = (write_index >= read_index)
	                          ? (write_index - read_index)
	                          : (CIRC_BUF_SIZE - read_index + write_index);

	                      if (available < 5) {
	                          break; // attendre plus de données
	                      }

	                      // Copie 5 octets
	                      for (int i = 0; i < 5; i++) {
	                          temp5[i] = circular_buffer[(read_index + i) % CIRC_BUF_SIZE];
	                      }

	                      // Confirmation TX ? (trame parasite)
	                      if (temp5[0] == 0x02 && temp5[1] == 0x40 && temp5[2] == 0x01) {
	                          // Skip trame de confirmation
	                          read_index = (read_index + 5) % CIRC_BUF_SIZE;
	                          continue;
	                      }

	                      // Sinon : partie utile, on ajoute à la trame
	                      for (int i = 0; i < 5 && data_index < TRAME_SIZE; i++) {
	                          temp_trame[data_index++] = temp5[i];
	                      }

	                      read_index = (read_index + 5) % CIRC_BUF_SIZE;
	                  }

	                  if (data_index == TRAME_SIZE) {

	                	  if (tarvos_checksum(temp_trame, TRAME_SIZE) == temp_trame[TRAME_SIZE - 1]) {

#ifdef PARTIE_HAUT
	                      memcpy(tarvos_DATA, temp_trame, TRAME_SIZE);
	                      decode_payload(&OTHERData, tarvos_DATA);  // ou un seul struct global

#endif

#ifdef PARTIE_BAS
	                      memcpy(tarvos_DATA, temp_trame, TRAME_SIZE);
	                      decode_payload(&TOPData, tarvos_DATA);  // ou un seul struct global

#endif

	                	  }

	                  }
	              } else {
	                  // Entête invalide : skip 1 octet
	                  read_index = (read_index + 1) % CIRC_BUF_SIZE;
	              }
	          }

		if(flag_fin==1){

			osThreadSuspend(NULL);
		}

		  uint32_t end1= DWT->CYCCNT;
		  uint32_t cycles= end1-start1;

		  timedecode=(float) cycles/(SystemCoreClock/1000000.0f);

vTaskDelay(pdMS_TO_TICKS(50));
  }
  /* USER CODE END startTarvosDecode */
}

/* USER CODE BEGIN Application */
//
//	  if(trameready==1){
//
//		  switch(tarvos_DATA[3]){
//#ifdef PARTIE_BAS
//		  case TOP_ADDR:
//			  decode_payload(&TOPData,(uint8_t *) tarvos_DATA);
//			  break;
//#endif
//		  default:
//			  decode_payload(&OTHERData,(uint8_t *) tarvos_DATA);
//
//			  break;
//		  }
//		  trameready=0;
//	  }
/* USER CODE END Application */
